VERSION 5.7 ;
  NOWIREEXTENSIONATPIN ON ;
  DIVIDERCHAR "/" ;
  BUSBITCHARS "[]" ;
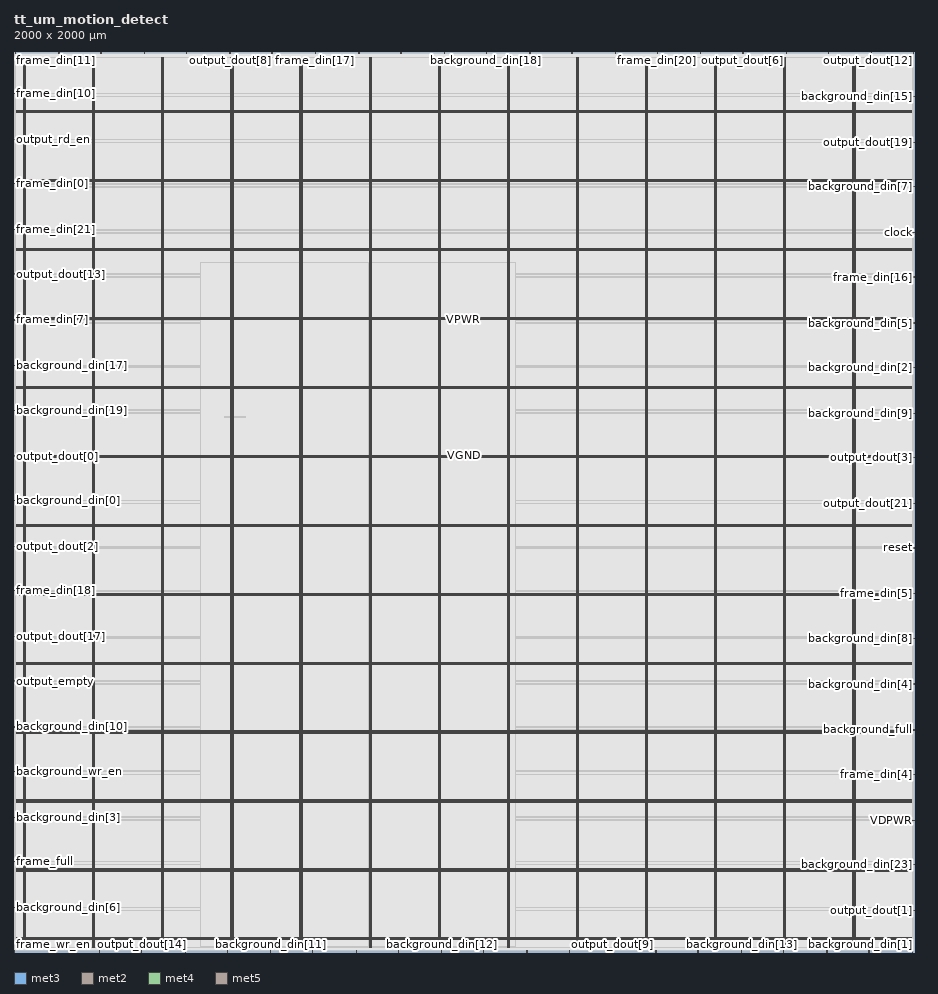
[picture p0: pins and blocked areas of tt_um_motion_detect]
MACRO tt_um_motion_detect
  CLASS BLOCK ;
  FOREIGN tt_um_motion_detect ;
  ORIGIN 0.000 0.000 ;
  SIZE 2000.000 BY 2000.000 ;
  PIN VDPWR
    DIRECTION INPUT ;
    USE SIGNAL ;
    PORT
      LAYER met3 ;
        RECT 1996.000 292.440 2000.000 293.040 ;
    END
  END VDPWR
  PIN VGND
    DIRECTION INPUT ;
    USE SIGNAL ;
    PORT
      LAYER met2 ;
        RECT 1809.730 1996.000 1810.010 2000.000 ;
    END
    PORT
      LAYER met4 ;
        RECT 24.340 10.640 25.940 1988.560 ;
    END
    PORT
      LAYER met4 ;
        RECT 177.940 10.640 179.540 1988.560 ;
    END
    PORT
      LAYER met4 ;
        RECT 331.540 10.640 333.140 1988.560 ;
    END
    PORT
      LAYER met4 ;
        RECT 485.140 10.640 486.740 1988.560 ;
    END
    PORT
      LAYER met4 ;
        RECT 638.740 10.640 640.340 1988.560 ;
    END
    PORT
      LAYER met4 ;
        RECT 792.340 10.640 793.940 1988.560 ;
    END
    PORT
      LAYER met4 ;
        RECT 945.940 10.640 947.540 1988.560 ;
    END
    PORT
      LAYER met4 ;
        RECT 1099.540 10.640 1101.140 1988.560 ;
    END
    PORT
      LAYER met4 ;
        RECT 1253.140 10.640 1254.740 1988.560 ;
    END
    PORT
      LAYER met4 ;
        RECT 1406.740 10.640 1408.340 1988.560 ;
    END
    PORT
      LAYER met4 ;
        RECT 1560.340 10.640 1561.940 1988.560 ;
    END
    PORT
      LAYER met4 ;
        RECT 1713.940 10.640 1715.540 1988.560 ;
    END
    PORT
      LAYER met4 ;
        RECT 1867.540 10.640 1869.140 1988.560 ;
    END
    PORT
      LAYER met5 ;
        RECT 5.280 30.030 1994.340 31.630 ;
    END
    PORT
      LAYER met5 ;
        RECT 5.280 183.210 1994.340 184.810 ;
    END
    PORT
      LAYER met5 ;
        RECT 5.280 336.390 1994.340 337.990 ;
    END
    PORT
      LAYER met5 ;
        RECT 5.280 489.570 1994.340 491.170 ;
    END
    PORT
      LAYER met5 ;
        RECT 5.280 642.750 1994.340 644.350 ;
    END
    PORT
      LAYER met5 ;
        RECT 5.280 795.930 1994.340 797.530 ;
    END
    PORT
      LAYER met5 ;
        RECT 5.280 949.110 1994.340 950.710 ;
    END
    PORT
      LAYER met5 ;
        RECT 5.280 1102.290 1994.340 1103.890 ;
    END
    PORT
      LAYER met5 ;
        RECT 5.280 1255.470 1994.340 1257.070 ;
    END
    PORT
      LAYER met5 ;
        RECT 5.280 1408.650 1994.340 1410.250 ;
    END
    PORT
      LAYER met5 ;
        RECT 5.280 1561.830 1994.340 1563.430 ;
    END
    PORT
      LAYER met5 ;
        RECT 5.280 1715.010 1994.340 1716.610 ;
    END
    PORT
      LAYER met5 ;
        RECT 5.280 1868.190 1994.340 1869.790 ;
    END
  END VGND
  PIN VPWR
    DIRECTION INOUT ;
    USE POWER ;
    PORT
      LAYER met4 ;
        RECT 21.040 10.640 22.640 1988.560 ;
    END
    PORT
      LAYER met4 ;
        RECT 174.640 10.640 176.240 1988.560 ;
    END
    PORT
      LAYER met4 ;
        RECT 328.240 10.640 329.840 1988.560 ;
    END
    PORT
      LAYER met4 ;
        RECT 481.840 10.640 483.440 1988.560 ;
    END
    PORT
      LAYER met4 ;
        RECT 635.440 10.640 637.040 1988.560 ;
    END
    PORT
      LAYER met4 ;
        RECT 789.040 10.640 790.640 1988.560 ;
    END
    PORT
      LAYER met4 ;
        RECT 942.640 10.640 944.240 1988.560 ;
    END
    PORT
      LAYER met4 ;
        RECT 1096.240 10.640 1097.840 1988.560 ;
    END
    PORT
      LAYER met4 ;
        RECT 1249.840 10.640 1251.440 1988.560 ;
    END
    PORT
      LAYER met4 ;
        RECT 1403.440 10.640 1405.040 1988.560 ;
    END
    PORT
      LAYER met4 ;
        RECT 1557.040 10.640 1558.640 1988.560 ;
    END
    PORT
      LAYER met4 ;
        RECT 1710.640 10.640 1712.240 1988.560 ;
    END
    PORT
      LAYER met4 ;
        RECT 1864.240 10.640 1865.840 1988.560 ;
    END
    PORT
      LAYER met5 ;
        RECT 5.280 26.730 1994.340 28.330 ;
    END
    PORT
      LAYER met5 ;
        RECT 5.280 179.910 1994.340 181.510 ;
    END
    PORT
      LAYER met5 ;
        RECT 5.280 333.090 1994.340 334.690 ;
    END
    PORT
      LAYER met5 ;
        RECT 5.280 486.270 1994.340 487.870 ;
    END
    PORT
      LAYER met5 ;
        RECT 5.280 639.450 1994.340 641.050 ;
    END
    PORT
      LAYER met5 ;
        RECT 5.280 792.630 1994.340 794.230 ;
    END
    PORT
      LAYER met5 ;
        RECT 5.280 945.810 1994.340 947.410 ;
    END
    PORT
      LAYER met5 ;
        RECT 5.280 1098.990 1994.340 1100.590 ;
    END
    PORT
      LAYER met5 ;
        RECT 5.280 1252.170 1994.340 1253.770 ;
    END
    PORT
      LAYER met5 ;
        RECT 5.280 1405.350 1994.340 1406.950 ;
    END
    PORT
      LAYER met5 ;
        RECT 5.280 1558.530 1994.340 1560.130 ;
    END
    PORT
      LAYER met5 ;
        RECT 5.280 1711.710 1994.340 1713.310 ;
    END
    PORT
      LAYER met5 ;
        RECT 5.280 1864.890 1994.340 1866.490 ;
    END
  END VPWR
  PIN background_din[0]
    DIRECTION INPUT ;
    USE SIGNAL ;
    PORT
      LAYER met3 ;
        RECT 0.000 1003.040 4.000 1003.640 ;
    END
  END background_din[0]
  PIN background_din[10]
    DIRECTION INPUT ;
    USE SIGNAL ;
    PORT
      LAYER met3 ;
        RECT 0.000 499.840 4.000 500.440 ;
    END
  END background_din[10]
  PIN background_din[11]
    DIRECTION INPUT ;
    USE SIGNAL ;
    PORT
      LAYER met2 ;
        RECT 570.030 0.000 570.310 4.000 ;
    END
  END background_din[11]
  PIN background_din[12]
    DIRECTION INPUT ;
    USE SIGNAL ;
    PORT
      LAYER met2 ;
        RECT 949.990 0.000 950.270 4.000 ;
    END
  END background_din[12]
  PIN background_din[13]
    DIRECTION INPUT ;
    USE SIGNAL ;
    PORT
      LAYER met2 ;
        RECT 1616.530 0.000 1616.810 4.000 ;
    END
  END background_din[13]
  PIN background_din[14]
    DIRECTION INPUT ;
    USE SIGNAL ;
    PORT
      LAYER met2 ;
        RECT 1709.910 0.000 1710.190 4.000 ;
    END
  END background_din[14]
  PIN background_din[15]
    DIRECTION INPUT ;
    USE SIGNAL ;
    PORT
      LAYER met3 ;
        RECT 1996.000 1900.640 2000.000 1901.240 ;
    END
  END background_din[15]
  PIN background_din[16]
    DIRECTION INPUT ;
    USE SIGNAL ;
    PORT
      LAYER met2 ;
        RECT 289.890 1996.000 290.170 2000.000 ;
    END
  END background_din[16]
  PIN background_din[17]
    DIRECTION INPUT ;
    USE SIGNAL ;
    PORT
      LAYER met3 ;
        RECT 0.000 1302.240 4.000 1302.840 ;
    END
  END background_din[17]
  PIN background_din[18]
    DIRECTION INPUT ;
    USE SIGNAL ;
    PORT
      LAYER met2 ;
        RECT 1049.810 1996.000 1050.090 2000.000 ;
    END
  END background_din[18]
  PIN background_din[19]
    DIRECTION INPUT ;
    USE SIGNAL ;
    PORT
      LAYER met3 ;
        RECT 0.000 1203.640 4.000 1204.240 ;
    END
  END background_din[19]
  PIN background_din[1]
    DIRECTION INPUT ;
    USE SIGNAL ;
    PORT
      LAYER met2 ;
        RECT 1996.490 0.000 1996.770 4.000 ;
    END
  END background_din[1]
  PIN background_din[20]
    DIRECTION INPUT ;
    USE SIGNAL ;
    PORT
      LAYER met2 ;
        RECT 1899.890 0.000 1900.170 4.000 ;
    END
  END background_din[20]
  PIN background_din[21]
    DIRECTION INPUT ;
    USE SIGNAL ;
    PORT
      LAYER met2 ;
        RECT 1146.410 1996.000 1146.690 2000.000 ;
    END
  END background_din[21]
  PIN background_din[22]
    DIRECTION INPUT ;
    USE SIGNAL ;
    PORT
      LAYER met2 ;
        RECT 1526.370 1996.000 1526.650 2000.000 ;
    END
  END background_din[22]
  PIN background_din[23]
    DIRECTION INPUT ;
    USE SIGNAL ;
    PORT
      LAYER met3 ;
        RECT 1996.000 193.840 2000.000 194.440 ;
    END
  END background_din[23]
  PIN background_din[2]
    DIRECTION INPUT ;
    USE SIGNAL ;
    PORT
      LAYER met3 ;
        RECT 1996.000 1298.840 2000.000 1299.440 ;
    END
  END background_din[2]
  PIN background_din[3]
    DIRECTION INPUT ;
    USE SIGNAL ;
    PORT
      LAYER met3 ;
        RECT 0.000 299.240 4.000 299.840 ;
    END
  END background_din[3]
  PIN background_din[4]
    DIRECTION INPUT ;
    USE SIGNAL ;
    PORT
      LAYER met3 ;
        RECT 1996.000 595.040 2000.000 595.640 ;
    END
  END background_din[4]
  PIN background_din[5]
    DIRECTION INPUT ;
    USE SIGNAL ;
    PORT
      LAYER met3 ;
        RECT 1996.000 1397.440 2000.000 1398.040 ;
    END
  END background_din[5]
  PIN background_din[6]
    DIRECTION INPUT ;
    USE SIGNAL ;
    PORT
      LAYER met3 ;
        RECT 0.000 98.640 4.000 99.240 ;
    END
  END background_din[6]
  PIN background_din[7]
    DIRECTION INPUT ;
    USE SIGNAL ;
    PORT
      LAYER met3 ;
        RECT 1996.000 1700.040 2000.000 1700.640 ;
    END
  END background_din[7]
  PIN background_din[8]
    DIRECTION INPUT ;
    USE SIGNAL ;
    PORT
      LAYER met3 ;
        RECT 1996.000 697.040 2000.000 697.640 ;
    END
  END background_din[8]
  PIN background_din[9]
    DIRECTION INPUT ;
    USE SIGNAL ;
    PORT
      LAYER met3 ;
        RECT 1996.000 1196.840 2000.000 1197.440 ;
    END
  END background_din[9]
  PIN background_full
    DIRECTION OUTPUT TRISTATE ;
    USE SIGNAL ;
    ANTENNADIFFAREA 0.445500 ;
    PORT
      LAYER met3 ;
        RECT 1996.000 493.040 2000.000 493.640 ;
    END
  END background_full
  PIN background_wr_en
    DIRECTION INPUT ;
    USE SIGNAL ;
    ANTENNAGATEAREA 0.742500 ;
    PORT
      LAYER met3 ;
        RECT 0.000 401.240 4.000 401.840 ;
    END
  END background_wr_en
  PIN clock
    DIRECTION INPUT ;
    USE SIGNAL ;
    ANTENNAGATEAREA 0.990000 ;
    PORT
      LAYER met3 ;
        RECT 1996.000 1598.040 2000.000 1598.640 ;
    END
  END clock
  PIN frame_din[0]
    DIRECTION INPUT ;
    USE SIGNAL ;
    ANTENNAGATEAREA 0.852000 ;
    PORT
      LAYER met3 ;
        RECT 0.000 1706.840 4.000 1707.440 ;
    END
  END frame_din[0]
  PIN frame_din[10]
    DIRECTION INPUT ;
    USE SIGNAL ;
    ANTENNAGATEAREA 0.852000 ;
    PORT
      LAYER met3 ;
        RECT 0.000 1907.440 4.000 1908.040 ;
    END
  END frame_din[10]
  PIN frame_din[11]
    DIRECTION INPUT ;
    USE SIGNAL ;
    ANTENNAGATEAREA 0.990000 ;
    PORT
      LAYER met2 ;
        RECT 3.310 1996.000 3.590 2000.000 ;
    END
  END frame_din[11]
  PIN frame_din[12]
    DIRECTION INPUT ;
    USE SIGNAL ;
    ANTENNAGATEAREA 0.990000 ;
    PORT
      LAYER met2 ;
        RECT 190.070 0.000 190.350 4.000 ;
    END
  END frame_din[12]
  PIN frame_din[13]
    DIRECTION INPUT ;
    USE SIGNAL ;
    ANTENNAGATEAREA 0.990000 ;
    PORT
      LAYER met2 ;
        RECT 1239.790 1996.000 1240.070 2000.000 ;
    END
  END frame_din[13]
  PIN frame_din[14]
    DIRECTION INPUT ;
    USE SIGNAL ;
    ANTENNAGATEAREA 0.990000 ;
    PORT
      LAYER met2 ;
        RECT 760.010 0.000 760.290 4.000 ;
    END
  END frame_din[14]
  PIN frame_din[15]
    DIRECTION INPUT ;
    USE SIGNAL ;
    ANTENNAGATEAREA 0.990000 ;
    PORT
      LAYER met2 ;
        RECT 1233.350 0.000 1233.630 4.000 ;
    END
  END frame_din[15]
  PIN frame_din[16]
    DIRECTION INPUT ;
    USE SIGNAL ;
    ANTENNAGATEAREA 0.990000 ;
    PORT
      LAYER met3 ;
        RECT 1996.000 1499.440 2000.000 1500.040 ;
    END
  END frame_din[16]
  PIN frame_din[17]
    DIRECTION INPUT ;
    USE SIGNAL ;
    ANTENNAGATEAREA 0.742500 ;
    PORT
      LAYER met2 ;
        RECT 669.850 1996.000 670.130 2000.000 ;
    END
  END frame_din[17]
  PIN frame_din[18]
    DIRECTION INPUT ;
    USE SIGNAL ;
    ANTENNAGATEAREA 0.742500 ;
    PORT
      LAYER met3 ;
        RECT 0.000 802.440 4.000 803.040 ;
    END
  END frame_din[18]
  PIN frame_din[19]
    DIRECTION INPUT ;
    USE SIGNAL ;
    ANTENNAGATEAREA 0.852000 ;
    PORT
      LAYER met2 ;
        RECT 473.430 0.000 473.710 4.000 ;
    END
  END frame_din[19]
  PIN frame_din[1]
    DIRECTION INPUT ;
    USE SIGNAL ;
    ANTENNAGATEAREA 0.990000 ;
    PORT
      LAYER met2 ;
        RECT 1519.930 0.000 1520.210 4.000 ;
    END
  END frame_din[1]
  PIN frame_din[20]
    DIRECTION INPUT ;
    USE SIGNAL ;
    ANTENNAGATEAREA 0.990000 ;
    PORT
      LAYER met2 ;
        RECT 1429.770 1996.000 1430.050 2000.000 ;
    END
  END frame_din[20]
  PIN frame_din[21]
    DIRECTION INPUT ;
    USE SIGNAL ;
    ANTENNAGATEAREA 0.742500 ;
    PORT
      LAYER met3 ;
        RECT 0.000 1604.840 4.000 1605.440 ;
    END
  END frame_din[21]
  PIN frame_din[22]
    DIRECTION INPUT ;
    USE SIGNAL ;
    ANTENNAGATEAREA 0.990000 ;
    PORT
      LAYER met2 ;
        RECT 1139.970 0.000 1140.250 4.000 ;
    END
  END frame_din[22]
  PIN frame_din[23]
    DIRECTION INPUT ;
    USE SIGNAL ;
    ANTENNAGATEAREA 0.852000 ;
    PORT
      LAYER met2 ;
        RECT 99.910 1996.000 100.190 2000.000 ;
    END
  END frame_din[23]
  PIN frame_din[2]
    DIRECTION INPUT ;
    USE SIGNAL ;
    ANTENNAGATEAREA 0.990000 ;
    PORT
      LAYER met2 ;
        RECT 1806.510 0.000 1806.790 4.000 ;
    END
  END frame_din[2]
  PIN frame_din[3]
    DIRECTION INPUT ;
    USE SIGNAL ;
    ANTENNAGATEAREA 0.742500 ;
    PORT
      LAYER met2 ;
        RECT 766.450 1996.000 766.730 2000.000 ;
    END
  END frame_din[3]
  PIN frame_din[4]
    DIRECTION INPUT ;
    USE SIGNAL ;
    ANTENNAGATEAREA 0.990000 ;
    PORT
      LAYER met3 ;
        RECT 1996.000 394.440 2000.000 395.040 ;
    END
  END frame_din[4]
  PIN frame_din[5]
    DIRECTION INPUT ;
    USE SIGNAL ;
    ANTENNAGATEAREA 0.990000 ;
    PORT
      LAYER met3 ;
        RECT 1996.000 795.640 2000.000 796.240 ;
    END
  END frame_din[5]
  PIN frame_din[6]
    DIRECTION INPUT ;
    USE SIGNAL ;
    ANTENNAGATEAREA 0.990000 ;
    PORT
      LAYER met2 ;
        RECT 1426.550 0.000 1426.830 4.000 ;
    END
  END frame_din[6]
  PIN frame_din[7]
    DIRECTION INPUT ;
    USE SIGNAL ;
    ANTENNAGATEAREA 0.742500 ;
    PORT
      LAYER met3 ;
        RECT 0.000 1404.240 4.000 1404.840 ;
    END
  END frame_din[7]
  PIN frame_din[8]
    DIRECTION INPUT ;
    USE SIGNAL ;
    ANTENNAGATEAREA 0.742500 ;
    PORT
      LAYER met2 ;
        RECT 573.250 1996.000 573.530 2000.000 ;
    END
  END frame_din[8]
  PIN frame_din[9]
    DIRECTION INPUT ;
    USE SIGNAL ;
    ANTENNAGATEAREA 0.852000 ;
    PORT
      LAYER met2 ;
        RECT 956.430 1996.000 956.710 2000.000 ;
    END
  END frame_din[9]
  PIN frame_full
    DIRECTION OUTPUT TRISTATE ;
    USE SIGNAL ;
    ANTENNADIFFAREA 0.795200 ;
    PORT
      LAYER met3 ;
        RECT 0.000 200.640 4.000 201.240 ;
    END
  END frame_full
  PIN frame_wr_en
    DIRECTION INPUT ;
    USE SIGNAL ;
    ANTENNAGATEAREA 0.990000 ;
    PORT
      LAYER met2 ;
        RECT 0.090 0.000 0.370 4.000 ;
    END
  END frame_wr_en
  PIN output_dout[0]
    DIRECTION OUTPUT TRISTATE ;
    USE SIGNAL ;
    ANTENNADIFFAREA 0.795200 ;
    PORT
      LAYER met3 ;
        RECT 0.000 1101.640 4.000 1102.240 ;
    END
  END output_dout[0]
  PIN output_dout[10]
    DIRECTION OUTPUT TRISTATE ;
    USE SIGNAL ;
    ANTENNADIFFAREA 0.795200 ;
    PORT
      LAYER met2 ;
        RECT 859.830 1996.000 860.110 2000.000 ;
    END
  END output_dout[10]
  PIN output_dout[11]
    DIRECTION OUTPUT TRISTATE ;
    USE SIGNAL ;
    ANTENNADIFFAREA 0.795200 ;
    PORT
      LAYER met2 ;
        RECT 1336.390 1996.000 1336.670 2000.000 ;
    END
  END output_dout[11]
  PIN output_dout[12]
    DIRECTION OUTPUT TRISTATE ;
    USE SIGNAL ;
    ANTENNADIFFAREA 0.795200 ;
    PORT
      LAYER met2 ;
        RECT 1906.330 1996.000 1906.610 2000.000 ;
    END
  END output_dout[12]
  PIN output_dout[13]
    DIRECTION OUTPUT TRISTATE ;
    USE SIGNAL ;
    ANTENNADIFFAREA 0.795200 ;
    PORT
      LAYER met3 ;
        RECT 0.000 1506.240 4.000 1506.840 ;
    END
  END output_dout[13]
  PIN output_dout[14]
    DIRECTION OUTPUT TRISTATE ;
    USE SIGNAL ;
    ANTENNADIFFAREA 0.795200 ;
    PORT
      LAYER met2 ;
        RECT 283.450 0.000 283.730 4.000 ;
    END
  END output_dout[14]
  PIN output_dout[15]
    DIRECTION OUTPUT TRISTATE ;
    USE SIGNAL ;
    ANTENNADIFFAREA 0.795200 ;
    PORT
      LAYER met2 ;
        RECT 93.470 0.000 93.750 4.000 ;
    END
  END output_dout[15]
  PIN output_dout[16]
    DIRECTION OUTPUT TRISTATE ;
    USE SIGNAL ;
    ANTENNADIFFAREA 0.795200 ;
    PORT
      LAYER met2 ;
        RECT 1999.710 1996.000 1999.990 2000.000 ;
    END
  END output_dout[16]
  PIN output_dout[17]
    DIRECTION OUTPUT TRISTATE ;
    USE SIGNAL ;
    ANTENNADIFFAREA 0.795200 ;
    PORT
      LAYER met3 ;
        RECT 0.000 700.440 4.000 701.040 ;
    END
  END output_dout[17]
  PIN output_dout[18]
    DIRECTION OUTPUT TRISTATE ;
    USE SIGNAL ;
    ANTENNADIFFAREA 0.795200 ;
    PORT
      LAYER met2 ;
        RECT 853.390 0.000 853.670 4.000 ;
    END
  END output_dout[18]
  PIN output_dout[19]
    DIRECTION OUTPUT TRISTATE ;
    USE SIGNAL ;
    ANTENNADIFFAREA 0.445500 ;
    PORT
      LAYER met3 ;
        RECT 1996.000 1798.640 2000.000 1799.240 ;
    END
  END output_dout[19]
  PIN output_dout[1]
    DIRECTION OUTPUT TRISTATE ;
    USE SIGNAL ;
    ANTENNADIFFAREA 0.445500 ;
    PORT
      LAYER met3 ;
        RECT 1996.000 91.840 2000.000 92.440 ;
    END
  END output_dout[1]
  PIN output_dout[20]
    DIRECTION OUTPUT TRISTATE ;
    USE SIGNAL ;
    ANTENNADIFFAREA 0.795200 ;
    PORT
      LAYER met2 ;
        RECT 383.270 1996.000 383.550 2000.000 ;
    END
  END output_dout[20]
  PIN output_dout[21]
    DIRECTION OUTPUT TRISTATE ;
    USE SIGNAL ;
    ANTENNADIFFAREA 0.445500 ;
    PORT
      LAYER met3 ;
        RECT 1996.000 996.240 2000.000 996.840 ;
    END
  END output_dout[21]
  PIN output_dout[22]
    DIRECTION OUTPUT TRISTATE ;
    USE SIGNAL ;
    ANTENNADIFFAREA 0.795200 ;
    PORT
      LAYER met2 ;
        RECT 380.050 0.000 380.330 4.000 ;
    END
  END output_dout[22]
  PIN output_dout[23]
    DIRECTION OUTPUT TRISTATE ;
    USE SIGNAL ;
    ANTENNADIFFAREA 0.795200 ;
    PORT
      LAYER met2 ;
        RECT 663.410 0.000 663.690 4.000 ;
    END
  END output_dout[23]
  PIN output_dout[2]
    DIRECTION OUTPUT TRISTATE ;
    USE SIGNAL ;
    ANTENNADIFFAREA 0.795200 ;
    PORT
      LAYER met3 ;
        RECT 0.000 901.040 4.000 901.640 ;
    END
  END output_dout[2]
  PIN output_dout[3]
    DIRECTION OUTPUT TRISTATE ;
    USE SIGNAL ;
    ANTENNADIFFAREA 0.445500 ;
    PORT
      LAYER met3 ;
        RECT 1996.000 1098.240 2000.000 1098.840 ;
    END
  END output_dout[3]
  PIN output_dout[4]
    DIRECTION OUTPUT TRISTATE ;
    USE SIGNAL ;
    ANTENNADIFFAREA 0.795200 ;
    PORT
      LAYER met2 ;
        RECT 1043.370 0.000 1043.650 4.000 ;
    END
  END output_dout[4]
  PIN output_dout[5]
    DIRECTION OUTPUT TRISTATE ;
    USE SIGNAL ;
    ANTENNADIFFAREA 0.795200 ;
    PORT
      LAYER met2 ;
        RECT 1716.350 1996.000 1716.630 2000.000 ;
    END
  END output_dout[5]
  PIN output_dout[6]
    DIRECTION OUTPUT TRISTATE ;
    USE SIGNAL ;
    ANTENNADIFFAREA 0.795200 ;
    PORT
      LAYER met2 ;
        RECT 1619.750 1996.000 1620.030 2000.000 ;
    END
  END output_dout[6]
  PIN output_dout[7]
    DIRECTION OUTPUT TRISTATE ;
    USE SIGNAL ;
    ANTENNADIFFAREA 0.795200 ;
    PORT
      LAYER met2 ;
        RECT 193.290 1996.000 193.570 2000.000 ;
    END
  END output_dout[7]
  PIN output_dout[8]
    DIRECTION OUTPUT TRISTATE ;
    USE SIGNAL ;
    ANTENNADIFFAREA 0.795200 ;
    PORT
      LAYER met2 ;
        RECT 479.870 1996.000 480.150 2000.000 ;
    END
  END output_dout[8]
  PIN output_dout[9]
    DIRECTION OUTPUT TRISTATE ;
    USE SIGNAL ;
    ANTENNADIFFAREA 0.795200 ;
    PORT
      LAYER met2 ;
        RECT 1329.950 0.000 1330.230 4.000 ;
    END
  END output_dout[9]
  PIN output_empty
    DIRECTION OUTPUT TRISTATE ;
    USE SIGNAL ;
    ANTENNADIFFAREA 0.795200 ;
    PORT
      LAYER met3 ;
        RECT 0.000 601.840 4.000 602.440 ;
    END
  END output_empty
  PIN output_rd_en
    DIRECTION INPUT ;
    USE SIGNAL ;
    ANTENNAGATEAREA 0.990000 ;
    PORT
      LAYER met3 ;
        RECT 0.000 1805.440 4.000 1806.040 ;
    END
  END output_rd_en
  PIN reset
    DIRECTION INPUT ;
    USE SIGNAL ;
    ANTENNAGATEAREA 0.852000 ;
    PORT
      LAYER met3 ;
        RECT 1996.000 897.640 2000.000 898.240 ;
    END
  END reset
  OBS
      LAYER li1 ;
        RECT 5.520 10.795 1994.100 1988.405 ;
      LAYER met1 ;
        RECT 0.070 10.640 1999.550 1988.560 ;
      LAYER met2 ;
        RECT 0.100 1995.720 3.030 1996.000 ;
        RECT 3.870 1995.720 99.630 1996.000 ;
        RECT 100.470 1995.720 193.010 1996.000 ;
        RECT 193.850 1995.720 289.610 1996.000 ;
        RECT 290.450 1995.720 382.990 1996.000 ;
        RECT 383.830 1995.720 479.590 1996.000 ;
        RECT 480.430 1995.720 572.970 1996.000 ;
        RECT 573.810 1995.720 669.570 1996.000 ;
        RECT 670.410 1995.720 766.170 1996.000 ;
        RECT 767.010 1995.720 859.550 1996.000 ;
        RECT 860.390 1995.720 956.150 1996.000 ;
        RECT 956.990 1995.720 1049.530 1996.000 ;
        RECT 1050.370 1995.720 1146.130 1996.000 ;
        RECT 1146.970 1995.720 1239.510 1996.000 ;
        RECT 1240.350 1995.720 1336.110 1996.000 ;
        RECT 1336.950 1995.720 1429.490 1996.000 ;
        RECT 1430.330 1995.720 1526.090 1996.000 ;
        RECT 1526.930 1995.720 1619.470 1996.000 ;
        RECT 1620.310 1995.720 1716.070 1996.000 ;
        RECT 1716.910 1995.720 1809.450 1996.000 ;
        RECT 1810.290 1995.720 1906.050 1996.000 ;
        RECT 1906.890 1995.720 1999.430 1996.000 ;
        RECT 0.100 4.280 1999.920 1995.720 ;
        RECT 0.650 3.670 93.190 4.280 ;
        RECT 94.030 3.670 189.790 4.280 ;
        RECT 190.630 3.670 283.170 4.280 ;
        RECT 284.010 3.670 379.770 4.280 ;
        RECT 380.610 3.670 473.150 4.280 ;
        RECT 473.990 3.670 569.750 4.280 ;
        RECT 570.590 3.670 663.130 4.280 ;
        RECT 663.970 3.670 759.730 4.280 ;
        RECT 760.570 3.670 853.110 4.280 ;
        RECT 853.950 3.670 949.710 4.280 ;
        RECT 950.550 3.670 1043.090 4.280 ;
        RECT 1043.930 3.670 1139.690 4.280 ;
        RECT 1140.530 3.670 1233.070 4.280 ;
        RECT 1233.910 3.670 1329.670 4.280 ;
        RECT 1330.510 3.670 1426.270 4.280 ;
        RECT 1427.110 3.670 1519.650 4.280 ;
        RECT 1520.490 3.670 1616.250 4.280 ;
        RECT 1617.090 3.670 1709.630 4.280 ;
        RECT 1710.470 3.670 1806.230 4.280 ;
        RECT 1807.070 3.670 1899.610 4.280 ;
        RECT 1900.450 3.670 1996.210 4.280 ;
        RECT 1997.050 3.670 1999.920 4.280 ;
      LAYER met3 ;
        RECT 4.000 1908.440 1996.000 1988.485 ;
        RECT 4.400 1907.040 1996.000 1908.440 ;
        RECT 4.000 1901.640 1996.000 1907.040 ;
        RECT 4.000 1900.240 1995.600 1901.640 ;
        RECT 4.000 1806.440 1996.000 1900.240 ;
        RECT 4.400 1805.040 1996.000 1806.440 ;
        RECT 4.000 1799.640 1996.000 1805.040 ;
        RECT 4.000 1798.240 1995.600 1799.640 ;
        RECT 4.000 1707.840 1996.000 1798.240 ;
        RECT 4.400 1706.440 1996.000 1707.840 ;
        RECT 4.000 1701.040 1996.000 1706.440 ;
        RECT 4.000 1699.640 1995.600 1701.040 ;
        RECT 4.000 1605.840 1996.000 1699.640 ;
        RECT 4.400 1604.440 1996.000 1605.840 ;
        RECT 4.000 1599.040 1996.000 1604.440 ;
        RECT 4.000 1597.640 1995.600 1599.040 ;
        RECT 4.000 1507.240 1996.000 1597.640 ;
        RECT 4.400 1505.840 1996.000 1507.240 ;
        RECT 4.000 1500.440 1996.000 1505.840 ;
        RECT 4.000 1499.040 1995.600 1500.440 ;
        RECT 4.000 1405.240 1996.000 1499.040 ;
        RECT 4.400 1403.840 1996.000 1405.240 ;
        RECT 4.000 1398.440 1996.000 1403.840 ;
        RECT 4.000 1397.040 1995.600 1398.440 ;
        RECT 4.000 1303.240 1996.000 1397.040 ;
        RECT 4.400 1301.840 1996.000 1303.240 ;
        RECT 4.000 1299.840 1996.000 1301.840 ;
        RECT 4.000 1298.440 1995.600 1299.840 ;
        RECT 4.000 1204.640 1996.000 1298.440 ;
        RECT 4.400 1203.240 1996.000 1204.640 ;
        RECT 4.000 1197.840 1996.000 1203.240 ;
        RECT 4.000 1196.440 1995.600 1197.840 ;
        RECT 4.000 1102.640 1996.000 1196.440 ;
        RECT 4.400 1101.240 1996.000 1102.640 ;
        RECT 4.000 1099.240 1996.000 1101.240 ;
        RECT 4.000 1097.840 1995.600 1099.240 ;
        RECT 4.000 1004.040 1996.000 1097.840 ;
        RECT 4.400 1002.640 1996.000 1004.040 ;
        RECT 4.000 997.240 1996.000 1002.640 ;
        RECT 4.000 995.840 1995.600 997.240 ;
        RECT 4.000 902.040 1996.000 995.840 ;
        RECT 4.400 900.640 1996.000 902.040 ;
        RECT 4.000 898.640 1996.000 900.640 ;
        RECT 4.000 897.240 1995.600 898.640 ;
        RECT 4.000 803.440 1996.000 897.240 ;
        RECT 4.400 802.040 1996.000 803.440 ;
        RECT 4.000 796.640 1996.000 802.040 ;
        RECT 4.000 795.240 1995.600 796.640 ;
        RECT 4.000 701.440 1996.000 795.240 ;
        RECT 4.400 700.040 1996.000 701.440 ;
        RECT 4.000 698.040 1996.000 700.040 ;
        RECT 4.000 696.640 1995.600 698.040 ;
        RECT 4.000 602.840 1996.000 696.640 ;
        RECT 4.400 601.440 1996.000 602.840 ;
        RECT 4.000 596.040 1996.000 601.440 ;
        RECT 4.000 594.640 1995.600 596.040 ;
        RECT 4.000 500.840 1996.000 594.640 ;
        RECT 4.400 499.440 1996.000 500.840 ;
        RECT 4.000 494.040 1996.000 499.440 ;
        RECT 4.000 492.640 1995.600 494.040 ;
        RECT 4.000 402.240 1996.000 492.640 ;
        RECT 4.400 400.840 1996.000 402.240 ;
        RECT 4.000 395.440 1996.000 400.840 ;
        RECT 4.000 394.040 1995.600 395.440 ;
        RECT 4.000 300.240 1996.000 394.040 ;
        RECT 4.400 298.840 1996.000 300.240 ;
        RECT 4.000 293.440 1996.000 298.840 ;
        RECT 4.000 292.040 1995.600 293.440 ;
        RECT 4.000 201.640 1996.000 292.040 ;
        RECT 4.400 200.240 1996.000 201.640 ;
        RECT 4.000 194.840 1996.000 200.240 ;
        RECT 4.000 193.440 1995.600 194.840 ;
        RECT 4.000 99.640 1996.000 193.440 ;
        RECT 4.400 98.240 1996.000 99.640 ;
        RECT 4.000 92.840 1996.000 98.240 ;
        RECT 4.000 91.440 1995.600 92.840 ;
        RECT 4.000 10.715 1996.000 91.440 ;
      LAYER met4 ;
        RECT 414.295 11.735 481.440 1532.545 ;
        RECT 483.840 11.735 484.740 1532.545 ;
        RECT 487.140 11.735 635.040 1532.545 ;
        RECT 637.440 11.735 638.340 1532.545 ;
        RECT 640.740 11.735 788.640 1532.545 ;
        RECT 791.040 11.735 791.940 1532.545 ;
        RECT 794.340 11.735 942.240 1532.545 ;
        RECT 944.640 11.735 945.540 1532.545 ;
        RECT 947.940 11.735 1095.840 1532.545 ;
        RECT 1098.240 11.735 1099.140 1532.545 ;
        RECT 1101.540 11.735 1114.745 1532.545 ;
      LAYER met5 ;
        RECT 467.940 1187.500 513.700 1189.100 ;
  END
END tt_um_motion_detect
END LIBRARY

